VERSION 5.7 ;
  NOWIREEXTENSIONATPIN ON ;
  DIVIDERCHAR "/" ;
  BUSBITCHARS "[]" ;
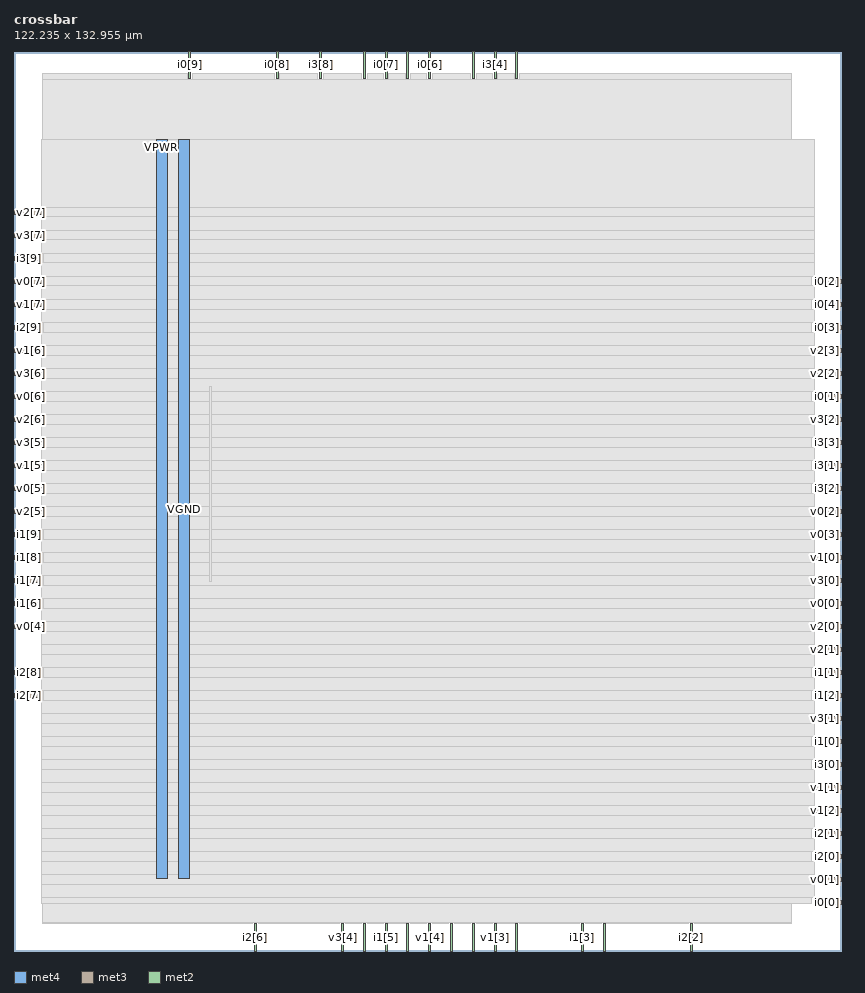
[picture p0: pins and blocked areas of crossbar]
MACRO crossbar
  CLASS BLOCK ;
  FOREIGN crossbar ;
  ORIGIN 0.000 0.000 ;
  SIZE 122.235 BY 132.955 ;
  PIN VGND
    DIRECTION INOUT ;
    USE GROUND ;
    PORT
      LAYER met4 ;
        RECT 24.340 10.640 25.940 119.920 ;
    END
  END VGND
  PIN VPWR
    DIRECTION INOUT ;
    USE POWER ;
    PORT
      LAYER met4 ;
        RECT 21.040 10.640 22.640 119.920 ;
    END
  END VPWR
  PIN i0[0]
    DIRECTION OUTPUT ;
    USE SIGNAL ;
    ANTENNADIFFAREA 0.445500 ;
    PORT
      LAYER met3 ;
        RECT 118.235 6.840 122.235 7.440 ;
    END
  END i0[0]
  PIN i0[1]
    DIRECTION OUTPUT ;
    USE SIGNAL ;
    ANTENNADIFFAREA 0.445500 ;
    PORT
      LAYER met3 ;
        RECT 118.235 81.640 122.235 82.240 ;
    END
  END i0[1]
  PIN i0[2]
    DIRECTION OUTPUT ;
    USE SIGNAL ;
    ANTENNADIFFAREA 0.445500 ;
    PORT
      LAYER met3 ;
        RECT 118.235 98.640 122.235 99.240 ;
    END
  END i0[2]
  PIN i0[3]
    DIRECTION OUTPUT ;
    USE SIGNAL ;
    ANTENNADIFFAREA 0.445500 ;
    PORT
      LAYER met3 ;
        RECT 118.235 91.840 122.235 92.440 ;
    END
  END i0[3]
  PIN i0[4]
    DIRECTION OUTPUT ;
    USE SIGNAL ;
    ANTENNADIFFAREA 0.445500 ;
    PORT
      LAYER met3 ;
        RECT 118.235 95.240 122.235 95.840 ;
    END
  END i0[4]
  PIN i0[5]
    DIRECTION OUTPUT ;
    USE SIGNAL ;
    ANTENNADIFFAREA 0.445500 ;
    PORT
      LAYER met2 ;
        RECT 74.150 128.955 74.430 132.955 ;
    END
  END i0[5]
  PIN i0[6]
    DIRECTION OUTPUT ;
    USE SIGNAL ;
    ANTENNADIFFAREA 0.445500 ;
    PORT
      LAYER met2 ;
        RECT 61.270 128.955 61.550 132.955 ;
    END
  END i0[6]
  PIN i0[7]
    DIRECTION OUTPUT ;
    USE SIGNAL ;
    ANTENNADIFFAREA 0.445500 ;
    PORT
      LAYER met2 ;
        RECT 54.830 128.955 55.110 132.955 ;
    END
  END i0[7]
  PIN i0[8]
    DIRECTION OUTPUT ;
    USE SIGNAL ;
    ANTENNADIFFAREA 0.445500 ;
    PORT
      LAYER met2 ;
        RECT 38.730 128.955 39.010 132.955 ;
    END
  END i0[8]
  PIN i0[9]
    DIRECTION OUTPUT ;
    USE SIGNAL ;
    ANTENNADIFFAREA 0.445500 ;
    PORT
      LAYER met2 ;
        RECT 25.850 128.955 26.130 132.955 ;
    END
  END i0[9]
  PIN i1[0]
    DIRECTION OUTPUT ;
    USE SIGNAL ;
    ANTENNADIFFAREA 0.445500 ;
    PORT
      LAYER met3 ;
        RECT 118.235 30.640 122.235 31.240 ;
    END
  END i1[0]
  PIN i1[1]
    DIRECTION OUTPUT ;
    USE SIGNAL ;
    ANTENNADIFFAREA 0.445500 ;
    PORT
      LAYER met3 ;
        RECT 118.235 40.840 122.235 41.440 ;
    END
  END i1[1]
  PIN i1[2]
    DIRECTION OUTPUT ;
    USE SIGNAL ;
    ANTENNADIFFAREA 0.445500 ;
    PORT
      LAYER met3 ;
        RECT 118.235 37.440 122.235 38.040 ;
    END
  END i1[2]
  PIN i1[3]
    DIRECTION OUTPUT ;
    USE SIGNAL ;
    ANTENNADIFFAREA 0.445500 ;
    PORT
      LAYER met2 ;
        RECT 83.810 0.000 84.090 4.000 ;
    END
  END i1[3]
  PIN i1[4]
    DIRECTION OUTPUT ;
    USE SIGNAL ;
    ANTENNADIFFAREA 0.445500 ;
    PORT
      LAYER met2 ;
        RECT 67.710 0.000 67.990 4.000 ;
    END
  END i1[4]
  PIN i1[5]
    DIRECTION OUTPUT ;
    USE SIGNAL ;
    ANTENNADIFFAREA 0.445500 ;
    PORT
      LAYER met2 ;
        RECT 54.830 0.000 55.110 4.000 ;
    END
  END i1[5]
  PIN i1[6]
    DIRECTION OUTPUT ;
    USE SIGNAL ;
    ANTENNADIFFAREA 0.445500 ;
    PORT
      LAYER met3 ;
        RECT 0.000 51.040 4.000 51.640 ;
    END
  END i1[6]
  PIN i1[7]
    DIRECTION OUTPUT ;
    USE SIGNAL ;
    ANTENNADIFFAREA 0.445500 ;
    PORT
      LAYER met3 ;
        RECT 0.000 54.440 4.000 55.040 ;
    END
  END i1[7]
  PIN i1[8]
    DIRECTION OUTPUT ;
    USE SIGNAL ;
    ANTENNADIFFAREA 0.445500 ;
    PORT
      LAYER met3 ;
        RECT 0.000 57.840 4.000 58.440 ;
    END
  END i1[8]
  PIN i1[9]
    DIRECTION OUTPUT ;
    USE SIGNAL ;
    ANTENNADIFFAREA 1.336500 ;
    PORT
      LAYER met3 ;
        RECT 0.000 61.240 4.000 61.840 ;
    END
  END i1[9]
  PIN i2[0]
    DIRECTION OUTPUT ;
    USE SIGNAL ;
    ANTENNADIFFAREA 0.445500 ;
    PORT
      LAYER met3 ;
        RECT 118.235 13.640 122.235 14.240 ;
    END
  END i2[0]
  PIN i2[1]
    DIRECTION OUTPUT ;
    USE SIGNAL ;
    ANTENNADIFFAREA 0.445500 ;
    PORT
      LAYER met3 ;
        RECT 118.235 17.040 122.235 17.640 ;
    END
  END i2[1]
  PIN i2[2]
    DIRECTION OUTPUT ;
    USE SIGNAL ;
    ANTENNADIFFAREA 0.445500 ;
    PORT
      LAYER met2 ;
        RECT 99.910 0.000 100.190 4.000 ;
    END
  END i2[2]
  PIN i2[3]
    DIRECTION OUTPUT ;
    USE SIGNAL ;
    ANTENNADIFFAREA 0.445500 ;
    PORT
      LAYER met2 ;
        RECT 87.030 0.000 87.310 4.000 ;
    END
  END i2[3]
  PIN i2[4]
    DIRECTION OUTPUT ;
    USE SIGNAL ;
    ANTENNADIFFAREA 0.445500 ;
    PORT
      LAYER met2 ;
        RECT 74.150 0.000 74.430 4.000 ;
    END
  END i2[4]
  PIN i2[5]
    DIRECTION OUTPUT ;
    USE SIGNAL ;
    ANTENNADIFFAREA 0.445500 ;
    PORT
      LAYER met2 ;
        RECT 58.050 0.000 58.330 4.000 ;
    END
  END i2[5]
  PIN i2[6]
    DIRECTION OUTPUT ;
    USE SIGNAL ;
    ANTENNADIFFAREA 0.445500 ;
    PORT
      LAYER met2 ;
        RECT 35.510 0.000 35.790 4.000 ;
    END
  END i2[6]
  PIN i2[7]
    DIRECTION OUTPUT ;
    USE SIGNAL ;
    ANTENNADIFFAREA 0.445500 ;
    PORT
      LAYER met3 ;
        RECT 0.000 37.440 4.000 38.040 ;
    END
  END i2[7]
  PIN i2[8]
    DIRECTION OUTPUT ;
    USE SIGNAL ;
    ANTENNADIFFAREA 0.445500 ;
    PORT
      LAYER met3 ;
        RECT 0.000 40.840 4.000 41.440 ;
    END
  END i2[8]
  PIN i2[9]
    DIRECTION OUTPUT ;
    USE SIGNAL ;
    ANTENNADIFFAREA 0.445500 ;
    PORT
      LAYER met3 ;
        RECT 0.000 91.840 4.000 92.440 ;
    END
  END i2[9]
  PIN i3[0]
    DIRECTION OUTPUT ;
    USE SIGNAL ;
    ANTENNADIFFAREA 0.445500 ;
    PORT
      LAYER met3 ;
        RECT 118.235 27.240 122.235 27.840 ;
    END
  END i3[0]
  PIN i3[1]
    DIRECTION OUTPUT ;
    USE SIGNAL ;
    ANTENNADIFFAREA 0.445500 ;
    PORT
      LAYER met3 ;
        RECT 118.235 71.440 122.235 72.040 ;
    END
  END i3[1]
  PIN i3[2]
    DIRECTION OUTPUT ;
    USE SIGNAL ;
    ANTENNADIFFAREA 0.445500 ;
    PORT
      LAYER met3 ;
        RECT 118.235 68.040 122.235 68.640 ;
    END
  END i3[2]
  PIN i3[3]
    DIRECTION OUTPUT ;
    USE SIGNAL ;
    ANTENNADIFFAREA 0.445500 ;
    PORT
      LAYER met3 ;
        RECT 118.235 74.840 122.235 75.440 ;
    END
  END i3[3]
  PIN i3[4]
    DIRECTION OUTPUT ;
    USE SIGNAL ;
    ANTENNADIFFAREA 0.445500 ;
    PORT
      LAYER met2 ;
        RECT 70.930 128.955 71.210 132.955 ;
    END
  END i3[4]
  PIN i3[5]
    DIRECTION OUTPUT ;
    USE SIGNAL ;
    ANTENNADIFFAREA 0.445500 ;
    PORT
      LAYER met2 ;
        RECT 67.710 128.955 67.990 132.955 ;
    END
  END i3[5]
  PIN i3[6]
    DIRECTION OUTPUT ;
    USE SIGNAL ;
    ANTENNADIFFAREA 0.445500 ;
    PORT
      LAYER met2 ;
        RECT 58.050 128.955 58.330 132.955 ;
    END
  END i3[6]
  PIN i3[7]
    DIRECTION OUTPUT ;
    USE SIGNAL ;
    ANTENNADIFFAREA 1.336500 ;
    PORT
      LAYER met2 ;
        RECT 51.610 128.955 51.890 132.955 ;
    END
  END i3[7]
  PIN i3[8]
    DIRECTION OUTPUT ;
    USE SIGNAL ;
    ANTENNADIFFAREA 1.336500 ;
    PORT
      LAYER met2 ;
        RECT 45.170 128.955 45.450 132.955 ;
    END
  END i3[8]
  PIN i3[9]
    DIRECTION OUTPUT ;
    USE SIGNAL ;
    ANTENNADIFFAREA 1.336500 ;
    PORT
      LAYER met3 ;
        RECT 0.000 102.040 4.000 102.640 ;
    END
  END i3[9]
  PIN v0[0]
    DIRECTION INPUT ;
    USE SIGNAL ;
    ANTENNAGATEAREA 0.495000 ;
    PORT
      LAYER met3 ;
        RECT 118.235 51.040 122.235 51.640 ;
    END
  END v0[0]
  PIN v0[1]
    DIRECTION INPUT ;
    USE SIGNAL ;
    ANTENNAGATEAREA 0.495000 ;
    PORT
      LAYER met3 ;
        RECT 118.235 10.240 122.235 10.840 ;
    END
  END v0[1]
  PIN v0[2]
    DIRECTION INPUT ;
    USE SIGNAL ;
    ANTENNAGATEAREA 0.213000 ;
    PORT
      LAYER met3 ;
        RECT 118.235 64.640 122.235 65.240 ;
    END
  END v0[2]
  PIN v0[3]
    DIRECTION INPUT ;
    USE SIGNAL ;
    ANTENNAGATEAREA 0.742500 ;
    PORT
      LAYER met3 ;
        RECT 118.235 61.240 122.235 61.840 ;
    END
  END v0[3]
  PIN v0[4]
    DIRECTION INPUT ;
    USE SIGNAL ;
    ANTENNAGATEAREA 0.159000 ;
    PORT
      LAYER met3 ;
        RECT 0.000 47.640 4.000 48.240 ;
    END
  END v0[4]
  PIN v0[5]
    DIRECTION INPUT ;
    USE SIGNAL ;
    ANTENNAGATEAREA 0.213000 ;
    PORT
      LAYER met3 ;
        RECT 0.000 68.040 4.000 68.640 ;
    END
  END v0[5]
  PIN v0[6]
    DIRECTION INPUT ;
    USE SIGNAL ;
    ANTENNAGATEAREA 0.213000 ;
    PORT
      LAYER met3 ;
        RECT 0.000 81.640 4.000 82.240 ;
    END
  END v0[6]
  PIN v0[7]
    DIRECTION INPUT ;
    USE SIGNAL ;
    ANTENNAGATEAREA 0.159000 ;
    PORT
      LAYER met3 ;
        RECT 0.000 98.640 4.000 99.240 ;
    END
  END v0[7]
  PIN v1[0]
    DIRECTION INPUT ;
    USE SIGNAL ;
    ANTENNAGATEAREA 0.196500 ;
    PORT
      LAYER met3 ;
        RECT 118.235 57.840 122.235 58.440 ;
    END
  END v1[0]
  PIN v1[1]
    DIRECTION INPUT ;
    USE SIGNAL ;
    ANTENNAGATEAREA 0.159000 ;
    PORT
      LAYER met3 ;
        RECT 118.235 23.840 122.235 24.440 ;
    END
  END v1[1]
  PIN v1[2]
    DIRECTION INPUT ;
    USE SIGNAL ;
    ANTENNAGATEAREA 0.159000 ;
    PORT
      LAYER met3 ;
        RECT 118.235 20.440 122.235 21.040 ;
    END
  END v1[2]
  PIN v1[3]
    DIRECTION INPUT ;
    USE SIGNAL ;
    ANTENNAGATEAREA 0.159000 ;
    PORT
      LAYER met2 ;
        RECT 70.930 0.000 71.210 4.000 ;
    END
  END v1[3]
  PIN v1[4]
    DIRECTION INPUT ;
    USE SIGNAL ;
    ANTENNAGATEAREA 0.213000 ;
    PORT
      LAYER met2 ;
        RECT 61.270 0.000 61.550 4.000 ;
    END
  END v1[4]
  PIN v1[5]
    DIRECTION INPUT ;
    USE SIGNAL ;
    ANTENNAGATEAREA 0.213000 ;
    PORT
      LAYER met3 ;
        RECT 0.000 71.440 4.000 72.040 ;
    END
  END v1[5]
  PIN v1[6]
    DIRECTION INPUT ;
    USE SIGNAL ;
    ANTENNAGATEAREA 0.213000 ;
    PORT
      LAYER met3 ;
        RECT 0.000 88.440 4.000 89.040 ;
    END
  END v1[6]
  PIN v1[7]
    DIRECTION INPUT ;
    USE SIGNAL ;
    ANTENNAGATEAREA 0.126000 ;
    PORT
      LAYER met3 ;
        RECT 0.000 95.240 4.000 95.840 ;
    END
  END v1[7]
  PIN v2[0]
    DIRECTION INPUT ;
    USE SIGNAL ;
    ANTENNAGATEAREA 0.159000 ;
    PORT
      LAYER met3 ;
        RECT 118.235 47.640 122.235 48.240 ;
    END
  END v2[0]
  PIN v2[1]
    DIRECTION INPUT ;
    USE SIGNAL ;
    ANTENNAGATEAREA 0.159000 ;
    PORT
      LAYER met3 ;
        RECT 118.235 44.240 122.235 44.840 ;
    END
  END v2[1]
  PIN v2[2]
    DIRECTION INPUT ;
    USE SIGNAL ;
    ANTENNAGATEAREA 0.159000 ;
    PORT
      LAYER met3 ;
        RECT 118.235 85.040 122.235 85.640 ;
    END
  END v2[2]
  PIN v2[3]
    DIRECTION INPUT ;
    USE SIGNAL ;
    ANTENNAGATEAREA 0.159000 ;
    PORT
      LAYER met3 ;
        RECT 118.235 88.440 122.235 89.040 ;
    END
  END v2[3]
  PIN v2[4]
    DIRECTION INPUT ;
    USE SIGNAL ;
    ANTENNAGATEAREA 0.159000 ;
    PORT
      LAYER met2 ;
        RECT 51.610 0.000 51.890 4.000 ;
    END
  END v2[4]
  PIN v2[5]
    DIRECTION INPUT ;
    USE SIGNAL ;
    ANTENNAGATEAREA 0.126000 ;
    PORT
      LAYER met3 ;
        RECT 0.000 64.640 4.000 65.240 ;
    END
  END v2[5]
  PIN v2[6]
    DIRECTION INPUT ;
    USE SIGNAL ;
    ANTENNAGATEAREA 0.126000 ;
    PORT
      LAYER met3 ;
        RECT 0.000 78.240 4.000 78.840 ;
    END
  END v2[6]
  PIN v2[7]
    DIRECTION INPUT ;
    USE SIGNAL ;
    ANTENNAGATEAREA 0.213000 ;
    PORT
      LAYER met3 ;
        RECT 0.000 108.840 4.000 109.440 ;
    END
  END v2[7]
  PIN v3[0]
    DIRECTION INPUT ;
    USE SIGNAL ;
    ANTENNAGATEAREA 0.213000 ;
    PORT
      LAYER met3 ;
        RECT 118.235 54.440 122.235 55.040 ;
    END
  END v3[0]
  PIN v3[1]
    DIRECTION INPUT ;
    USE SIGNAL ;
    ANTENNAGATEAREA 0.159000 ;
    PORT
      LAYER met3 ;
        RECT 118.235 34.040 122.235 34.640 ;
    END
  END v3[1]
  PIN v3[2]
    DIRECTION INPUT ;
    USE SIGNAL ;
    ANTENNAGATEAREA 0.159000 ;
    PORT
      LAYER met3 ;
        RECT 118.235 78.240 122.235 78.840 ;
    END
  END v3[2]
  PIN v3[3]
    DIRECTION INPUT ;
    USE SIGNAL ;
    ANTENNAGATEAREA 0.213000 ;
    PORT
      LAYER met2 ;
        RECT 64.490 0.000 64.770 4.000 ;
    END
  END v3[3]
  PIN v3[4]
    DIRECTION INPUT ;
    USE SIGNAL ;
    ANTENNAGATEAREA 0.159000 ;
    PORT
      LAYER met2 ;
        RECT 48.390 0.000 48.670 4.000 ;
    END
  END v3[4]
  PIN v3[5]
    DIRECTION INPUT ;
    USE SIGNAL ;
    ANTENNAGATEAREA 0.159000 ;
    PORT
      LAYER met3 ;
        RECT 0.000 74.840 4.000 75.440 ;
    END
  END v3[5]
  PIN v3[6]
    DIRECTION INPUT ;
    USE SIGNAL ;
    ANTENNAGATEAREA 0.159000 ;
    PORT
      LAYER met3 ;
        RECT 0.000 85.040 4.000 85.640 ;
    END
  END v3[6]
  PIN v3[7]
    DIRECTION INPUT ;
    USE SIGNAL ;
    ANTENNAGATEAREA 0.159000 ;
    PORT
      LAYER met3 ;
        RECT 0.000 105.440 4.000 106.040 ;
    END
  END v3[7]
  OBS
      LAYER nwell ;
        RECT 5.330 10.795 116.570 119.765 ;
      LAYER li1 ;
        RECT 5.520 10.795 116.380 119.765 ;
      LAYER met1 ;
        RECT 4.210 10.640 116.380 119.920 ;
      LAYER met2 ;
        RECT 4.230 128.675 25.570 129.610 ;
        RECT 26.410 128.675 38.450 129.610 ;
        RECT 39.290 128.675 44.890 129.610 ;
        RECT 45.730 128.675 51.330 129.610 ;
        RECT 52.170 128.675 54.550 129.610 ;
        RECT 55.390 128.675 57.770 129.610 ;
        RECT 58.610 128.675 60.990 129.610 ;
        RECT 61.830 128.675 67.430 129.610 ;
        RECT 68.270 128.675 70.650 129.610 ;
        RECT 71.490 128.675 73.870 129.610 ;
        RECT 74.710 128.675 114.910 129.610 ;
        RECT 4.230 4.280 114.910 128.675 ;
        RECT 4.230 4.000 35.230 4.280 ;
        RECT 36.070 4.000 48.110 4.280 ;
        RECT 48.950 4.000 51.330 4.280 ;
        RECT 52.170 4.000 54.550 4.280 ;
        RECT 55.390 4.000 57.770 4.280 ;
        RECT 58.610 4.000 60.990 4.280 ;
        RECT 61.830 4.000 64.210 4.280 ;
        RECT 65.050 4.000 67.430 4.280 ;
        RECT 68.270 4.000 70.650 4.280 ;
        RECT 71.490 4.000 73.870 4.280 ;
        RECT 74.710 4.000 83.530 4.280 ;
        RECT 84.370 4.000 86.750 4.280 ;
        RECT 87.590 4.000 99.630 4.280 ;
        RECT 100.470 4.000 114.910 4.280 ;
      LAYER met3 ;
        RECT 3.990 109.840 118.235 119.845 ;
        RECT 4.400 108.440 118.235 109.840 ;
        RECT 3.990 106.440 118.235 108.440 ;
        RECT 4.400 105.040 118.235 106.440 ;
        RECT 3.990 103.040 118.235 105.040 ;
        RECT 4.400 101.640 118.235 103.040 ;
        RECT 3.990 99.640 118.235 101.640 ;
        RECT 4.400 98.240 117.835 99.640 ;
        RECT 3.990 96.240 118.235 98.240 ;
        RECT 4.400 94.840 117.835 96.240 ;
        RECT 3.990 92.840 118.235 94.840 ;
        RECT 4.400 91.440 117.835 92.840 ;
        RECT 3.990 89.440 118.235 91.440 ;
        RECT 4.400 88.040 117.835 89.440 ;
        RECT 3.990 86.040 118.235 88.040 ;
        RECT 4.400 84.640 117.835 86.040 ;
        RECT 3.990 82.640 118.235 84.640 ;
        RECT 4.400 81.240 117.835 82.640 ;
        RECT 3.990 79.240 118.235 81.240 ;
        RECT 4.400 77.840 117.835 79.240 ;
        RECT 3.990 75.840 118.235 77.840 ;
        RECT 4.400 74.440 117.835 75.840 ;
        RECT 3.990 72.440 118.235 74.440 ;
        RECT 4.400 71.040 117.835 72.440 ;
        RECT 3.990 69.040 118.235 71.040 ;
        RECT 4.400 67.640 117.835 69.040 ;
        RECT 3.990 65.640 118.235 67.640 ;
        RECT 4.400 64.240 117.835 65.640 ;
        RECT 3.990 62.240 118.235 64.240 ;
        RECT 4.400 60.840 117.835 62.240 ;
        RECT 3.990 58.840 118.235 60.840 ;
        RECT 4.400 57.440 117.835 58.840 ;
        RECT 3.990 55.440 118.235 57.440 ;
        RECT 4.400 54.040 117.835 55.440 ;
        RECT 3.990 52.040 118.235 54.040 ;
        RECT 4.400 50.640 117.835 52.040 ;
        RECT 3.990 48.640 118.235 50.640 ;
        RECT 4.400 47.240 117.835 48.640 ;
        RECT 3.990 45.240 118.235 47.240 ;
        RECT 3.990 43.840 117.835 45.240 ;
        RECT 3.990 41.840 118.235 43.840 ;
        RECT 4.400 40.440 117.835 41.840 ;
        RECT 3.990 38.440 118.235 40.440 ;
        RECT 4.400 37.040 117.835 38.440 ;
        RECT 3.990 35.040 118.235 37.040 ;
        RECT 3.990 33.640 117.835 35.040 ;
        RECT 3.990 31.640 118.235 33.640 ;
        RECT 3.990 30.240 117.835 31.640 ;
        RECT 3.990 28.240 118.235 30.240 ;
        RECT 3.990 26.840 117.835 28.240 ;
        RECT 3.990 24.840 118.235 26.840 ;
        RECT 3.990 23.440 117.835 24.840 ;
        RECT 3.990 21.440 118.235 23.440 ;
        RECT 3.990 20.040 117.835 21.440 ;
        RECT 3.990 18.040 118.235 20.040 ;
        RECT 3.990 16.640 117.835 18.040 ;
        RECT 3.990 14.640 118.235 16.640 ;
        RECT 3.990 13.240 117.835 14.640 ;
        RECT 3.990 11.240 118.235 13.240 ;
        RECT 3.990 9.840 117.835 11.240 ;
        RECT 3.990 7.840 118.235 9.840 ;
        RECT 3.990 6.975 117.835 7.840 ;
      LAYER met4 ;
        RECT 28.815 54.575 29.145 83.465 ;
  END
END crossbar
END LIBRARY

